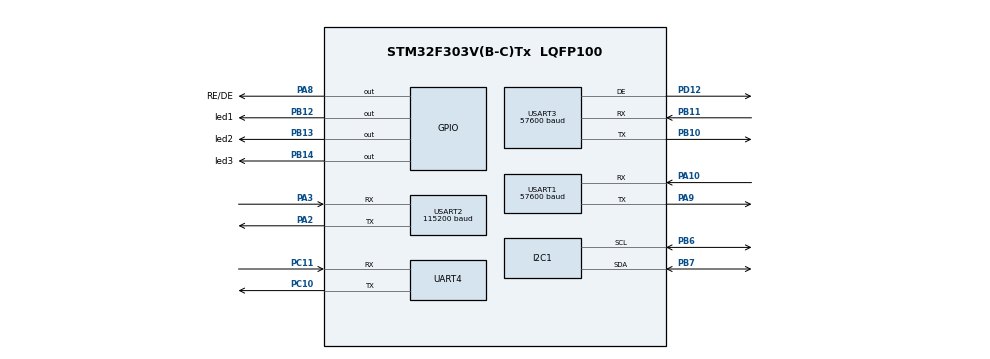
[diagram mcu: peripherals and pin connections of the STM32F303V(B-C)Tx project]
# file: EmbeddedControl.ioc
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Dma.Request0=USART1_RX
Dma.Request1=USART1_TX
Dma.Request2=USART2_TX
Dma.Request3=USART2_RX
Dma.Request4=USART3_RX
Dma.Request5=USART3_TX
Dma.USART1_RX.0.Direction=DMA_PERIPH_TO_MEMORY
Dma.USART1_RX.0.Instance=DMA1_Channel5
Dma.USART1_RX.0.MemDataAlignment=DMA_MDATAALIGN_BYTE
Dma.USART1_RX.0.MemInc=DMA_MINC_ENABLE
Dma.USART1_RX.0.Mode=DMA_NORMAL
Dma.USART1_RX.0.PeriphDataAlignment=DMA_PDATAALIGN_BYTE
Dma.USART1_RX.0.PeriphInc=DMA_PINC_DISABLE
Dma.USART1_RX.0.Priority=DMA_PRIORITY_VERY_HIGH
Dma.USART1_TX.1.Direction=DMA_MEMORY_TO_PERIPH
Dma.USART1_TX.1.Instance=DMA1_Channel4
Dma.USART1_TX.1.MemDataAlignment=DMA_MDATAALIGN_BYTE
Dma.USART1_TX.1.MemInc=DMA_MINC_ENABLE
Dma.USART1_TX.1.Mode=DMA_NORMAL
Dma.USART1_TX.1.PeriphDataAlignment=DMA_PDATAALIGN_BYTE
Dma.USART1_TX.1.PeriphInc=DMA_PINC_DISABLE
Dma.USART1_TX.1.Priority=DMA_PRIORITY_VERY_HIGH
Dma.USART2_RX.3.Direction=DMA_PERIPH_TO_MEMORY
Dma.USART2_RX.3.Instance=DMA1_Channel6
Dma.USART2_RX.3.MemDataAlignment=DMA_MDATAALIGN_BYTE
Dma.USART2_RX.3.MemInc=DMA_MINC_ENABLE
Dma.USART2_RX.3.Mode=DMA_NORMAL
Dma.USART2_RX.3.PeriphDataAlignment=DMA_PDATAALIGN_BYTE
Dma.USART2_RX.3.PeriphInc=DMA_PINC_DISABLE
Dma.USART2_RX.3.Priority=DMA_PRIORITY_VERY_HIGH
Dma.USART2_TX.2.Direction=DMA_MEMORY_TO_PERIPH
Dma.USART2_TX.2.Instance=DMA1_Channel7
Dma.USART2_TX.2.MemDataAlignment=DMA_MDATAALIGN_BYTE
Dma.USART2_TX.2.MemInc=DMA_MINC_ENABLE
Dma.USART2_TX.2.Mode=DMA_NORMAL
Dma.USART2_TX.2.PeriphDataAlignment=DMA_PDATAALIGN_BYTE
Dma.USART2_TX.2.PeriphInc=DMA_PINC_DISABLE
Dma.USART2_TX.2.Priority=DMA_PRIORITY_LOW
Dma.USART3_RX.4.Direction=DMA_PERIPH_TO_MEMORY
Dma.USART3_RX.4.Instance=DMA1_Channel3
Dma.USART3_RX.4.MemDataAlignment=DMA_MDATAALIGN_BYTE
Dma.USART3_RX.4.MemInc=DMA_MINC_ENABLE
Dma.USART3_RX.4.Mode=DMA_NORMAL
Dma.USART3_RX.4.PeriphDataAlignment=DMA_PDATAALIGN_BYTE
Dma.USART3_RX.4.PeriphInc=DMA_PINC_DISABLE
Dma.USART3_RX.4.Priority=DMA_PRIORITY_HIGH
Dma.USART3_TX.5.Direction=DMA_MEMORY_TO_PERIPH
Dma.USART3_TX.5.Instance=DMA1_Channel2
Dma.USART3_TX.5.MemDataAlignment=DMA_MDATAALIGN_BYTE
Dma.USART3_TX.5.MemInc=DMA_MINC_ENABLE
Dma.USART3_TX.5.Mode=DMA_NORMAL
Dma.USART3_TX.5.PeriphDataAlignment=DMA_PDATAALIGN_BYTE
Dma.USART3_TX.5.PeriphInc=DMA_PINC_DISABLE
Dma.USART3_TX.5.Priority=DMA_PRIORITY_HIGH
FREERTOS.INCLUDE_vTaskDelayUntil=1
FREERTOS.MEMORY_ALLOCATION=2
FREERTOS.Mutexes01=mutData,Static,mutDataControlBlock
FREERTOS.Tasks01=tLedBlinkingTask,-2,128,func_tLedBlinkingTask,Default,NULL,Static,tLedBlinkingTaskBuffer,tLedBlinkingTaskControlBlock;tVmaCommTask,-1,128,func_tVmaCommTask,Default,NULL,Static,tVmaCommTaskBuffer,tVmaCommTaskControlBlock;tImuCommTask,-1,128,func_tImuCommTask,Default,NULL,Static,tImuCommTaskBuffer,tImuCommTaskControlBlock;tStabilizationTask,-1,128,func_tStabilizationTask,Default,NULL,Static,tStabilizationTaskBuffer,tStabilizationTaskControlBlock;tDevCommTask,-1,128,func_tDevCommTask,Default,NULL,Static,tDevCommTaskBuffer,tDevCommTaskControlBlock;tSensCommTask,-1,128,func_tSensCommTask,Default,NULL,Static,tSensCommTaskBuffer,tSensCommTaskControlBlock;tPcCommTask,-1,128,func_tPcCommTask,Default,NULL,Static,tPcCommTaskBuffer,tPcCommTaskControlBlock
FREERTOS.Timers01=tUartTimer,func_tUartTimer,osTimerOnce,Default,NULL,Dynamic,NULL;tSilence,tSilence_func,osTimerOnce,Default,NULL,Dynamic,NULL;tTechCommTImer,tTechCommTImer_callback,osTimerOnce,Default,NULL,Dynamic,NULL
FREERTOS.configMAX_PRIORITIES=4
FREERTOS.configMAX_TASK_NAME_LEN=32
FREERTOS.configTOTAL_HEAP_SIZE=1024
FREERTOS.configUSE_MUTEXES=1
FREERTOS.configUSE_NEWLIB_REENTRANT=1
FREERTOS.configUSE_TIMERS=1
I2C1.Timing=0x10808DD3
Mcu.Family=STM32F3
Mcu.Name=STM32F303V(B-C)Tx
Mcu.Package=LQFP100
NVIC.DMA1_Channel2_IRQn=true\:5\:0\:false\:false\:true\:true\:false\:true\:true
NVIC.DMA1_Channel3_IRQn=true\:5\:0\:false\:false\:true\:true\:false\:true\:true
NVIC.DMA1_Channel4_IRQn=true\:5\:0\:false\:false\:true\:true\:false\:true\:true
NVIC.DMA1_Channel5_IRQn=true\:5\:0\:false\:false\:true\:true\:false\:true\:true
NVIC.DMA1_Channel6_IRQn=true\:5\:0\:false\:false\:true\:true\:false\:true\:true
NVIC.DMA1_Channel7_IRQn=true\:5\:0\:false\:false\:true\:true\:false\:true\:true
NVIC.I2C1_EV_IRQn=true\:5\:0\:false\:false\:true\:true\:true\:true\:true
NVIC.PriorityGroup=NVIC_PRIORITYGROUP_4
NVIC.TIM1_UP_TIM16_IRQn=true\:0\:0\:true\:false\:true\:false\:false\:true\:true
NVIC.TimeBase=TIM1_UP_TIM16_IRQn
NVIC.TimeBaseIP=TIM1
NVIC.UART4_IRQn=true\:5\:0\:false\:false\:true\:true\:true\:true\:true
NVIC.USART1_IRQn=true\:5\:0\:false\:false\:true\:true\:true\:true\:true
NVIC.USART2_IRQn=true\:5\:0\:false\:false\:true\:true\:true\:true\:true
NVIC.USART3_IRQn=true\:5\:0\:false\:false\:true\:true\:true\:true\:true
PA10.GPIO_PuPd=GPIO_PULLUP
PA10.Mode=Asynchronous
PA10.Signal=USART1_RX
PA12.Signal=CAN_TX
PA13.Mode=Trace_Asynchronous_SW
PA13.Signal=SYS_JTMS-SWDIO
PA14.GPIO_Label=SWCLK
PA14.Mode=Trace_Asynchronous_SW
PA14.Signal=SYS_JTCK-SWCLK
PA2.GPIO_PuPd=GPIO_PULLUP
PA2.Mode=Asynchronous
PA2.Signal=USART2_TX
PA3.GPIO_PuPd=GPIO_PULLUP
PA3.Mode=Asynchronous
PA3.Signal=USART2_RX
PA8.GPIO_Label=RE/DE
PA8.Signal=GPIO_Output
PA9.GPIO_PuPd=GPIO_PULLUP
PA9.Mode=Asynchronous
PA9.Signal=USART1_TX
PB10.GPIO_PuPd=GPIO_PULLUP
PB10.Mode=Asynchronous
PB10.Signal=USART3_TX
PB11.GPIO_PuPd=GPIO_PULLUP
PB11.Mode=Asynchronous
PB11.Signal=USART3_RX
PB12.GPIO_Label=led1
PB12.Signal=GPIO_Output
PB13.GPIO_Label=led2
PB13.Signal=GPIO_Output
PB14.GPIO_Label=led3
PB14.Signal=GPIO_Output
PB3.GPIO_Label=SWO
PB3.Mode=Trace_Asynchronous_SW
PB3.Signal=SYS_JTDO-TRACESWO
PB6.Mode=I2C
PB6.Signal=I2C1_SCL
PB7.Mode=I2C
PB7.Signal=I2C1_SDA
PC10.Mode=Asynchronous
PC10.Signal=UART4_TX
PC11.Mode=Asynchronous
PC11.Signal=UART4_RX
PD12.Mode=Hardware Flow Control (RS485)
PD12.Signal=USART3_DE
PF0-OSC_IN.GPIO_Label=OSC_IN
PF0-OSC_IN.Mode=HSE-External-Oscillator
PF0-OSC_IN.Signal=RCC_OSC_IN
PF1-OSC_OUT.GPIO_Label=OSC_OUT
PF1-OSC_OUT.Mode=HSE-External-Oscillator
PF1-OSC_OUT.Signal=RCC_OSC_OUT
ProjectManager.HeapSize=0x200
ProjectManager.StackSize=0x400
ProjectManager.TargetToolchain=STM32CubeIDE
RCC.AHBFreq_Value=72000000
RCC.APB1CLKDivider=RCC_HCLK_DIV2
RCC.APB1Freq_Value=36000000
RCC.APB1TimFreq_Value=72000000
RCC.APB2Freq_Value=72000000
RCC.APB2TimFreq_Value=72000000
RCC.CortexFreq_Value=72000000
RCC.HCLKFreq_Value=72000000
RCC.HSE_VALUE=8000000
RCC.HSI_VALUE=8000000
RCC.I2c1ClockSelection=RCC_I2C1CLKSOURCE_SYSCLK
RCC.LSE_VALUE=32768
RCC.PLLMUL=RCC_PLL_MUL9
RCC.PLLSourceVirtual=RCC_PLLSOURCE_HSE
RCC.SYSCLKFreq_VALUE=72000000
RCC.SYSCLKSourceVirtual=RCC_SYSCLKSOURCE_PLLCLK
RCC.USBFreq_Value=72000000
RCC.Uart4ClockSelection=RCC_UART4CLKSOURCE_SYSCLK
RCC.Usart2ClockSelection=RCC_USART2CLKSOURCE_SYSCLK
RCC.Usart3ClockSelection=RCC_USART3CLKSOURCE_SYSCLK
USART1.BaudRate=57600
USART1.DMADisableonRxErrorParam=ADVFEATURE_DMA_ENABLEONRXERROR
USART1.VirtualMode-Asynchronous=VM_ASYNC
USART2.BaudRate=115200
USART2.DMADisableonRxErrorParam=ADVFEATURE_DMA_DISABLEONRXERROR
USART2.VirtualMode-Asynchronous=VM_ASYNC
USART3.BaudRate=57600
USART3.DMADisableonRxErrorParam=ADVFEATURE_DMA_ENABLEONRXERROR
USART3.SwapParam=ADVFEATURE_SWAP_DISABLE
USART3.VirtualMode-Asynchronous=VM_ASYNC
USART3.VirtualMode-Hardware\ Flow\ Control\ (RS485)=VM_ASYNC
VP_FREERTOS_VS_CMSIS_V1.Mode=CMSIS_V1
VP_SYS_VS_tim1.Mode=TIM1
VP_TIM7_VS_ClockSourceINT.Mode=Enable_Timer
board=STM32F3DISCOVERY

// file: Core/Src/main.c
/* USER CODE BEGIN Header */
/**
  ******************************************************************************
  * @file           : main.c
  * @brief          : Main program body
  ******************************************************************************
  * @attention
  *
  * Copyright (c) 2023 STMicroelectronics.
  * All rights reserved.
  *
  * This software is licensed under terms that can be found in the LICENSE file
  * in the root directory of this software component.
  * If no LICENSE file comes with this software, it is provided AS-IS.
  *
  ******************************************************************************
  */
/* USER CODE END Header */
#include "main.h"
#include "cmsis_os.h"
#include "dma.h"
#include "i2c.h"
#include "tim.h"
#include "usart.h"
#include "gpio.h"
#include "thrusters.h"
#include "communication.h"

void SystemClock_Config(void);
void MX_FREERTOS_Init(void);

int main(void)
{

  /* MCU Configuration--------------------------------------------------------*/

  /* Reset of all peripherals, Initializes the Flash interface and the Systick. */
  HAL_Init();

  /* Configure the system clock */
  SystemClock_Config();

  /* Initialize all configured peripherals */
  MX_GPIO_Init();
  MX_DMA_Init();
  MX_I2C1_Init();
  MX_UART4_Init();
  MX_USART1_UART_Init();
  MX_USART2_UART_Init();
  MX_USART3_UART_Init();
  MX_TIM7_Init();
  /* USER CODE BEGIN 2 */
  //HAL_Delay(10e3);
  uint8_t transaction = 0;
  uint8_t ThrustersRequestBuffer0[] = {0xAA, 0x1, 0xAF, 0x00, 0x00, 0x00, 0x00, 0x0, 0x0, 0x0, 0x0, 0x0, 0xae};
  uint8_t ThrustersRequestBuffer1[] = {0xAA, 0x1, 0xAF, 0xb, 0xf0, 0xb, 0xf0, 0x10, 0xf0, 0xb, 0x10, 0x0, 0x55};

  uint8_t ThrustersRequestBuffer2[] =  {0xAA, 0x1, 0xAF, 0x17, 0xdd, 0xf1, 0x17, 0xe9, 0x17, 0x17, 0x23, 0x0, 0x48};
  uint8_t ThrustersRequestBuffer3[] = {0xAA, 0x1, 0xAF, 0xd, 0x14, 0xf3, 0xec, 0xec, 0xec, 0xf3, 0x14, 0x0, 0x4f};
 // uint8_t ThrustersRequestBuffer4[] = {0xAA, 0x1, 0xAF, 0xb, 0xf0, 0xb, 0xf0, 0x10, 0xf0, 0xb, 0x10, 0x0, 0x55};
  uint8_t ThrustersResponseBuffer[THRUSTERS_NUMBER][THRUSTERS_RESPONSE_LENGTH];
  HAL_GPIO_WritePin(RE_DE_GPIO_Port,RE_DE_Pin,GPIO_PIN_SET);

  //HAL_UART_Receive_(&huart1, ThrustersResponseBuffer[transaction], THRUSTERS_RESPONSE_LENGTH);
  HAL_UART_Transmit(&huart1, ThrustersRequestBuffer0, THRUSTERS_REQUEST_LENGTH,100);
  HAL_Delay(6000);

  HAL_UART_Transmit(&huart1, ThrustersRequestBuffer1, THRUSTERS_REQUEST_LENGTH,100);

  HAL_Delay(14000);

  HAL_UART_Transmit(&huart1, ThrustersRequestBuffer0, THRUSTERS_REQUEST_LENGTH,100);

  HAL_Delay(1000);

  HAL_UART_Transmit(&huart1, ThrustersRequestBuffer2, THRUSTERS_REQUEST_LENGTH,100);

  HAL_Delay(10000);

  HAL_UART_Transmit(&huart1, ThrustersRequestBuffer3, THRUSTERS_REQUEST_LENGTH,100);
  HAL_Delay(300);

  HAL_UART_Transmit(&huart1, ThrustersRequestBuffer2, THRUSTERS_REQUEST_LENGTH,100);

  HAL_Delay(10000);

 // HAL_Delay(5000);
  /* USER CODE END 2 */

  /* Call init function for freertos objects (in freertos.c) */
//  MX_FREERTOS_Init();

  /* Start scheduler */
//  osKernelStart();

  /* We should never get here as control is now taken by the scheduler */
  /* Infinite loop */
  while (1)
  {

  }
}

void SystemClock_Config(void)
{
  RCC_OscInitTypeDef RCC_OscInitStruct = {0};
  RCC_ClkInitTypeDef RCC_ClkInitStruct = {0};

  /** Configure the main internal regulator output voltage
  */
  __HAL_RCC_PWR_CLK_ENABLE();
  __HAL_PWR_VOLTAGESCALING_CONFIG(PWR_REGULATOR_VOLTAGE_SCALE1);

  /** Initializes the RCC Oscillators according to the specified parameters
  * in the RCC_OscInitTypeDef structure.
  */
  RCC_OscInitStruct.OscillatorType = RCC_OSCILLATORTYPE_HSI;
  RCC_OscInitStruct.HSIState = RCC_HSI_ON;
  RCC_OscInitStruct.HSICalibrationValue = RCC_HSICALIBRATION_DEFAULT;
  RCC_OscInitStruct.PLL.PLLState = RCC_PLL_ON;
  RCC_OscInitStruct.PLL.PLLSource = RCC_PLLSOURCE_HSI;
  RCC_OscInitStruct.PLL.PLLM = 8;
  RCC_OscInitStruct.PLL.PLLN = 75;
  RCC_OscInitStruct.PLL.PLLP = RCC_PLLP_DIV2;
  RCC_OscInitStruct.PLL.PLLQ = 4;
  if (HAL_RCC_OscConfig(&RCC_OscInitStruct) != HAL_OK)
  {
    Error_Handler();
  }

  /** Initializes the CPU, AHB and APB buses clocks
  */
  RCC_ClkInitStruct.ClockType = RCC_CLOCKTYPE_HCLK|RCC_CLOCKTYPE_SYSCLK
                              |RCC_CLOCKTYPE_PCLK1|RCC_CLOCKTYPE_PCLK2;
  RCC_ClkInitStruct.SYSCLKSource = RCC_SYSCLKSOURCE_PLLCLK;
  RCC_ClkInitStruct.AHBCLKDivider = RCC_SYSCLK_DIV1;
  RCC_ClkInitStruct.APB1CLKDivider = RCC_HCLK_DIV2;
  RCC_ClkInitStruct.APB2CLKDivider = RCC_HCLK_DIV1;

  if (HAL_RCC_ClockConfig(&RCC_ClkInitStruct, FLASH_LATENCY_2) != HAL_OK)
  {
    Error_Handler();
  }
}

void HAL_TIM_PeriodElapsedCallback(TIM_HandleTypeDef *htim)
{
  if (htim->Instance == TIM1) {
    HAL_IncTick();
  }
}

void Error_Handler(void)
{
  __disable_irq();
  while (1)
  {
  }
}
